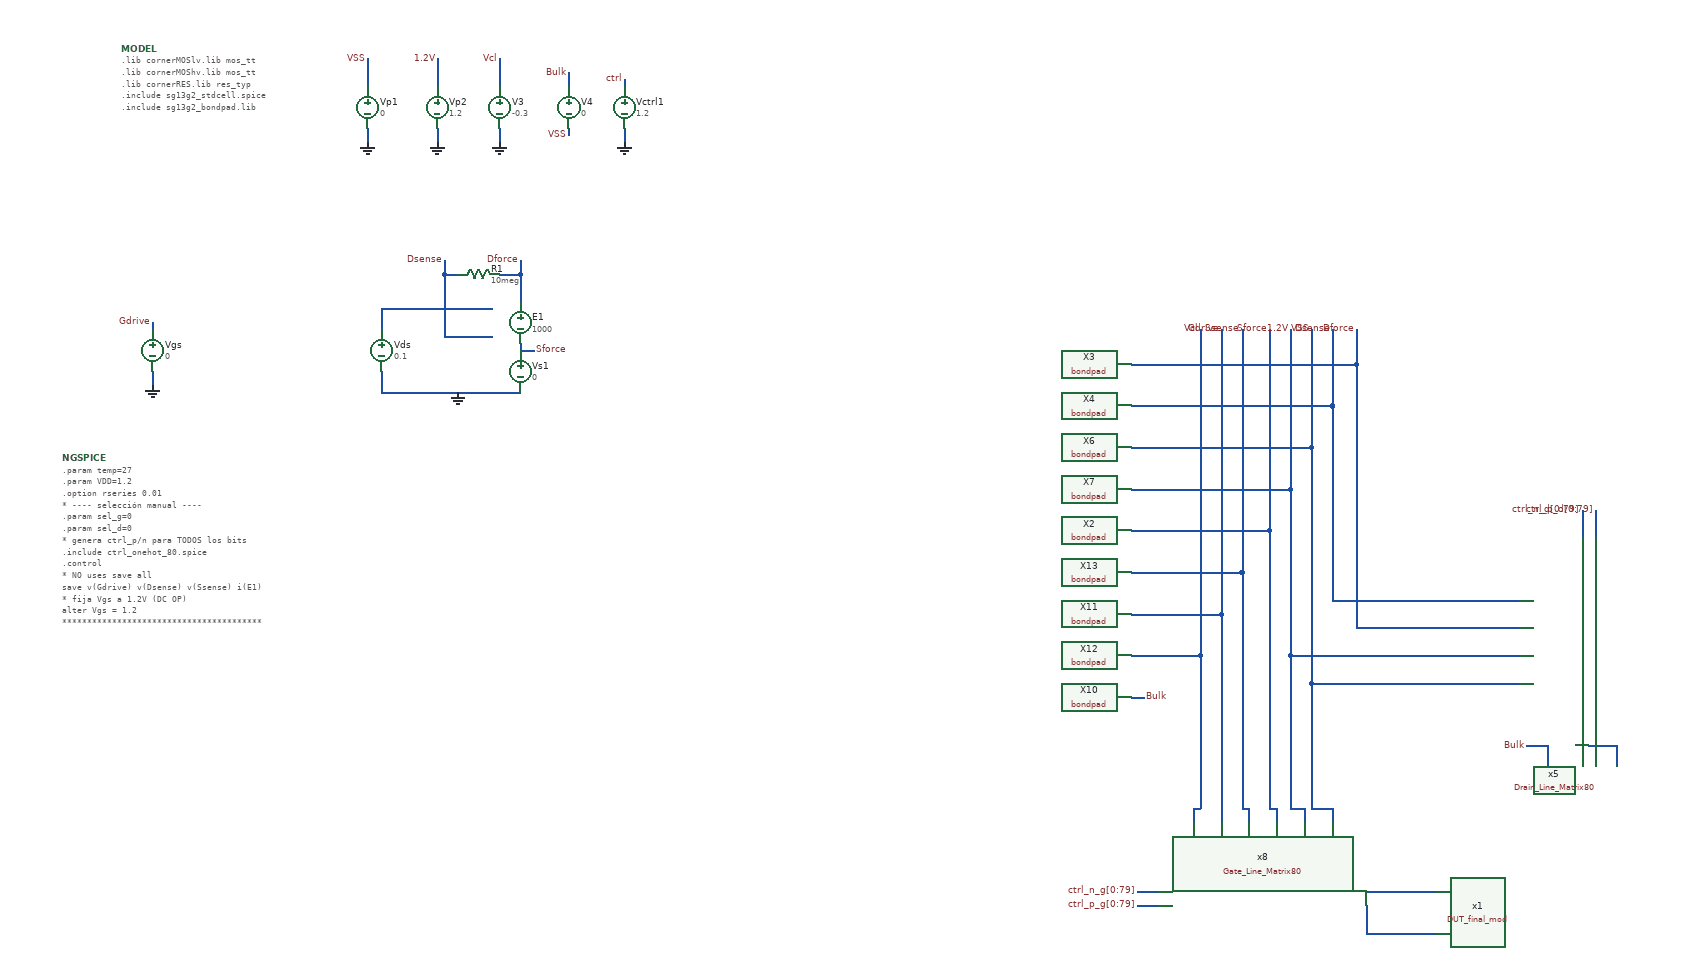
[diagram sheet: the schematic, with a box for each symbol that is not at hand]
v {xschem version=3.4.6 file_version=1.2}
G {}
K {}
V {}
S {}
E {}
B 2 395 -925 1195 -525 {flags=graph

y2=1.8
ypos1=0
ypos2=2
divy=5
subdivy=1
unity=1
x1=-2.28
x2=-1.08
divx=5
subdivx=1

dataset=-1
unitx=1
logx=0
logy=0


y1=0.3
rainbow=0

color="6 7"
node="V(G1)

V(G2)"}
B 2 395 -1355 1195 -955 {flags=graph

y2=0.1034
ypos1=0
ypos2=2
divy=5
subdivy=4
unity=1
x1=-2.28
x2=-1.08
divx=5
subdivx=1

dataset=-1
unitx=1
logx=0
logy=0


y1=0.0924
rainbow=0



color="4 9 7"
node="D2
Dsense
Dforce"}
B 2 395 -505 1195 -105 {flags=graph

y2=0.00021
ypos1=0
ypos2=2
divy=5
subdivy=4
unity=1
x1=-2.28
x2=-1.08
divx=5
subdivx=1

dataset=-1
unitx=1
logx=0
logy=0


y1=-4.4e-10
rainbow=0

color="6 4"
node="i(Ids)
i(gm)"
mode=Line}
N 520 -1830 520 -1810 {
lab=GND}
N 520 -1930 520 -1890 {
lab=1.2V}
N 610 -1830 610 -1810 {
lab=GND}
N 610 -1930 610 -1890 {
lab=Vcl}
N 420 -1930 420 -1890 {
lab=VSS}
N 710 -1910 710 -1890 {lab=Bulk}
N 420 -1830 420 -1810 {lab=GND}
N 710 -1830 710 -1820 {lab=VSS}
N 440 -1570 600 -1570 {lab=#net1}
N 610 -1620 640 -1620 {lab=Dforce}
N 640 -1620 640 -1580 {lab=Dforce}
N 640 -1640 640 -1620 {lab=Dforce}
N 530 -1620 550 -1620 {lab=Dsense}
N 530 -1620 530 -1530 {lab=Dsense}
N 530 -1530 600 -1530 {lab=Dsense}
N 530 -1640 530 -1620 {lab=Dsense}
N 640 -1510 660 -1510 {lab=Sforce}
N 640 -1520 640 -1510 {lab=Sforce}
N 440 -1450 640 -1450 {lab=GND}
N 440 -1480 440 -1450 {lab=GND}
N 440 -1570 440 -1540 {lab=#net1}
N 2190 -1280 2190 -1240 {lab=ctrl_p_d[0:79]}
N 2170 -1280 2170 -1240 {lab=ctrl_n_d[0:79]}
N 1530 -730 1560 -730 {lab=ctrl_n_g[0:79]}
N 1530 -710 1560 -710 {lab=ctrl_p_g[0:79]}
N 790 -1830 790 -1810 {
lab=GND}
N 790 -1900 790 -1890 {
lab=ctrl}
N 110 -1480 110 -1460 {
lab=GND}
N 110 -1550 110 -1540 {
lab=Gdrive}
N 1520 -1010 1540 -1010 {lab=Bulk}
N 2090 -940 2120 -940 {lab=Bulk}
N 2120 -940 2120 -910 {lab=Bulk}
N 1520 -1250 1720 -1250 {lab=Sforce}
N 1520 -1190 1680 -1190 {lab=Ssense}
N 1520 -1130 1650 -1130 {lab=Gdrive}
N 1520 -1070 1620 -1070 {lab=Vcl}
N 1620 -1070 1620 -850 {lab=Vcl}
N 1650 -1130 1650 -830 {lab=Gdrive}
N 1680 -1190 1680 -850 {lab=Ssense}
N 1720 -1250 1720 -850 {lab=Sforce}
N 1520 -1310 1750 -1310 {lab=1.2V}
N 1520 -1370 1780 -1370 {lab=VSS}
N 1750 -1540 1750 -1310 {lab=1.2V}
N 1620 -1540 1620 -1070 {lab=Vcl}
N 1650 -1540 1650 -1130 {lab=Gdrive}
N 1680 -1540 1680 -1190 {lab=Ssense}
N 1720 -1540 1720 -1250 {lab=Sforce}
N 1810 -1430 1810 -1150 {lab=Dsense}
N 1845 -1490 1845 -1110 {lab=Dforce}
N 1810 -1540 1810 -1430 {lab=Dsense}
N 1845 -1540 1845 -1490 {lab=Dforce}
N 1520 -1430 1810 -1430 {lab=Dsense}
N 1520 -1490 1845 -1490 {lab=Dforce}
N 1780 -1030 1780 -850 {lab=VSS}
N 1780 -1540 1780 -1370 {lab=VSS}
N 1750 -1070 2080 -1070 {lab=1.2V}
N 1750 -1070 1750 -850 {lab=1.2V}
N 1750 -1310 1750 -1070 {lab=1.2V}
N 1780 -1030 2080 -1030 {lab=VSS}
N 1780 -1370 1780 -1030 {lab=VSS}
N 1810 -1150 2080 -1150 {lab=Dsense}
N 1845 -1110 2080 -1110 {lab=Dforce}
N 1610 -850 1620 -850 {lab=Vcl}
N 1610 -850 1610 -830 {lab=Vcl}
N 1680 -850 1690 -850 {lab=Ssense}
N 1690 -850 1690 -830 {lab=Ssense}
N 1720 -850 1730 -850 {lab=Sforce}
N 1730 -850 1730 -830 {lab=Sforce}
N 1750 -850 1770 -850 {lab=1.2V}
N 1770 -850 1770 -830 {lab=1.2V}
N 1780 -850 1810 -850 {lab=VSS}
N 1810 -850 1810 -830 {lab=VSS}
N 2180 -940 2220 -940 {lab=#net2}
N 2220 -940 2220 -910 {lab=#net2}
N 1860 -730 1960 -730 {lab=#net3}
N 1860 -710 1860 -670 {lab=#net4}
N 1860 -670 1960 -670 {lab=#net4}
C {devices/code_shown.sym} 65 -1945 0 0 {name=MODEL only_toplevel=true
format="tcleval( @value )"
value="
.lib cornerMOSlv.lib mos_tt\\
.lib cornerMOShv.lib mos_tt\\
.lib cornerRES.lib res_typ\\
.include sg13g2_stdcell.spice
.include sg13g2_bondpad.lib
"}
C {devices/code_shown.sym} -20 -1355 0 0 {name=NGSPICE only_toplevel=true
value="
.param temp=27
.param VDD=1.2
.option rseries 0.01

* ---- selección manual ----
.param sel_g=0
.param sel_d=0

* genera ctrl_p/n para TODOS los bits
.include ctrl_onehot_80.spice

.control
* NO uses save all
save v(Gdrive) v(Dsense) v(Ssense) i(E1)

* fija Vgs a 1.2V (DC OP)
alter Vgs = 1.2

****************************************
* CASO 1: ON (sel_g, sel_d)
****************************************
echo CASE_ON
op
let Ids  = -I(E1)
let VdsK = v(Dsense)-v(Ssense)
print sel_g sel_d Ids VdsK v(Gdrive)

****************************************
* CASO 2: OFF (sel=-1 => ningún bit coincide)
****************************************
echo CASE_OFF
alterparam sel_g = -1
alterparam sel_d = -1
op
let Ids_off  = -I(E1)
let VdsK_off = v(Dsense)-v(Ssense)
print sel_g sel_d Ids_off VdsK_off v(Gdrive)

****************************************
* CASO 3: OTRO transistor
****************************************
echo CASE_ON2
alterparam sel_g = 1
alterparam sel_d = 1
op
let Ids2  = -I(E1)
let VdsK2 = v(Dsense)-v(Ssense)
print sel_g sel_d Ids2 VdsK2 v(Gdrive)

write tb_opcheck.raw
.endc
"



}
C {devices/vsource.sym} 520 -1860 0 0 {name=Vp2 value=1.2}
C {devices/launcher.sym} 225 -135 0 0 {name=h5
descr="load waves" 
tclcommand="xschem raw_read $netlist_dir/tran_lshift.raw dc"
}
C {devices/gnd.sym} 520 -1810 0 0 {name=l1 lab=GND}
C {devices/lab_pin.sym} 520 -1930 1 0 {name=p4 sig_type=std_logic lab=1.2V}
C {devices/lab_pin.sym} 1750 -1540 1 0 {name=p2 sig_type=std_logic lab=1.2V}
C {devices/lab_pin.sym} 1650 -1540 1 0 {name=p6 sig_type=std_logic lab=Gdrive}
C {devices/lab_pin.sym} 1620 -1540 1 0 {name=p7 sig_type=std_logic lab=Vcl}
C {devices/vsource.sym} 610 -1860 0 0 {name=V3 value=-0.3}
C {devices/gnd.sym} 610 -1810 0 0 {name=l4 lab=GND}
C {devices/lab_pin.sym} 610 -1930 1 0 {name=p8 sig_type=std_logic lab=Vcl}
C {sg13g2_pr/bondpad.sym} 1480 -1250 3 0 {name=X2
model=bondpad
spiceprefix=X
size=80u
shape=0
padtype=0
}
C {sg13g2_pr/bondpad.sym} 1480 -1490 3 0 {name=X3
model=bondpad
spiceprefix=X
size=80u
shape=0
padtype=0
}
C {sg13g2_pr/bondpad.sym} 1480 -1430 3 0 {name=X4
model=bondpad
spiceprefix=X
size=80u
shape=0
padtype=0
}
C {sg13g2_pr/bondpad.sym} 1480 -1370 3 0 {name=X6
model=bondpad
spiceprefix=X
size=80u
shape=0
padtype=0
}
C {sg13g2_pr/bondpad.sym} 1480 -1310 3 0 {name=X7
model=bondpad
spiceprefix=X
size=80u
shape=0
padtype=0
}
C {devices/vsource.sym} 420 -1860 0 0 {name=Vp1 value=0}
C {devices/lab_pin.sym} 420 -1930 1 0 {name=p22 sig_type=std_logic lab=VSS}
C {devices/lab_pin.sym} 1780 -1540 1 0 {name=p10 sig_type=std_logic lab=VSS}
C {devices/lab_pin.sym} 1680 -1540 1 0 {name=p17 sig_type=std_logic lab=Ssense}
C {devices/lab_pin.sym} 1720 -1540 1 0 {name=p24 sig_type=std_logic lab=Sforce}
C {sg13g2_pr/bondpad.sym} 1480 -1010 3 0 {name=X10
model=bondpad
spiceprefix=X
size=80u
shape=0
padtype=0
}
C {devices/lab_pin.sym} 1540 -1010 2 0 {name=p25 sig_type=std_logic lab=Bulk}
C {devices/vsource.sym} 710 -1860 0 0 {name=V4 value=0}
C {devices/lab_pin.sym} 710 -1910 1 0 {name=p26 sig_type=std_logic lab=Bulk}
C {devices/lab_pin.sym} 710 -1820 3 0 {name=p27 sig_type=std_logic lab=VSS}
C {devices/gnd.sym} 420 -1810 0 0 {name=l2 lab=GND}
C {devices/lab_pin.sym} 1810 -1540 1 0 {name=p13 sig_type=std_logic lab=Dsense}
C {devices/lab_pin.sym} 1845 -1540 1 0 {name=p14 sig_type=std_logic lab=Dforce}
C {devices/lab_pin.sym} 640 -1640 1 0 {name=p18 sig_type=std_logic lab=Dforce}
C {devices/lab_pin.sym} 660 -1510 2 0 {name=p28 sig_type=std_logic lab=Sforce}
C {devices/vsource.sym} 640 -1480 0 0 {name=Vs1 value=0}
C {vcvs.sym} 640 -1550 0 0 {name=E1 value=1000}
C {devices/vsource.sym} 440 -1510 0 0 {name=Vds value=0.1}
C {res.sym} 580 -1620 3 0 {name=R1
value=10meg
footprint=1206
device=resistor
m=1}
C {devices/lab_pin.sym} 530 -1640 1 0 {name=p33 sig_type=std_logic lab=Dsense}
C {devices/gnd.sym} 550 -1450 0 0 {name=l6 lab=GND}
C {devices/lab_pin.sym} 1530 -730 0 0 {name=p5 sig_type=std_logic lab=ctrl_n_g[0:79]}
C {devices/vsource.sym} 790 -1860 0 0 {name=Vctrl1 value=1.2}
C {devices/gnd.sym} 790 -1810 0 0 {name=l5 lab=GND}
C {devices/lab_pin.sym} 790 -1900 1 0 {name=p1 sig_type=std_logic lab=ctrl}
C {devices/vsource.sym} 110 -1510 0 0 {name=Vgs value=0}
C {devices/gnd.sym} 110 -1460 0 0 {name=l7 lab=GND}
C {devices/lab_pin.sym} 110 -1550 1 0 {name=p35 sig_type=std_logic lab=Gdrive}
C {devices/lab_pin.sym} 1530 -710 0 0 {name=p15 sig_type=std_logic lab=ctrl_p_g[0:79]}
C {devices/lab_pin.sym} 2170 -1280 1 0 {name=p21 sig_type=std_logic lab=ctrl_n_d[0:79]}
C {devices/lab_pin.sym} 2190 -1280 1 0 {name=p34 sig_type=std_logic lab=ctrl_p_d[0:79]}
C {sg13g2_pr/bondpad.sym} 1480 -1190 3 0 {name=X13
model=bondpad
spiceprefix=X
size=80u
shape=0
padtype=0
}
C {sg13g2_pr/bondpad.sym} 1480 -1130 3 0 {name=X11
model=bondpad
spiceprefix=X
size=80u
shape=0
padtype=0
}
C {sg13g2_pr/bondpad.sym} 1480 -1070 3 0 {name=X12
model=bondpad
spiceprefix=X
size=80u
shape=0
padtype=0
}
C {devices/lab_pin.sym} 2090 -940 0 0 {name=p20 sig_type=std_logic lab=Bulk}
C {/home/designer/shared/verification/simulations/ihp-sg13g2/MissMatch/design_data/xschem/new_DUT/DUT_final_mod.sym} 2170 -700 0 0 {name=x1}
C {/home/designer/shared/verification/simulations/ihp-sg13g2/MissMatch/design_data/xschem/new_tg/Drain_Line_Matrix80.sym} 2180 -1090 1 0 {name=x5}
C {/home/designer/shared/verification/simulations/ihp-sg13g2/MissMatch/design_data/xschem/new_tg/Gate_Line_Matrix80.sym} 1710 -720 2 1 {name=x8}
